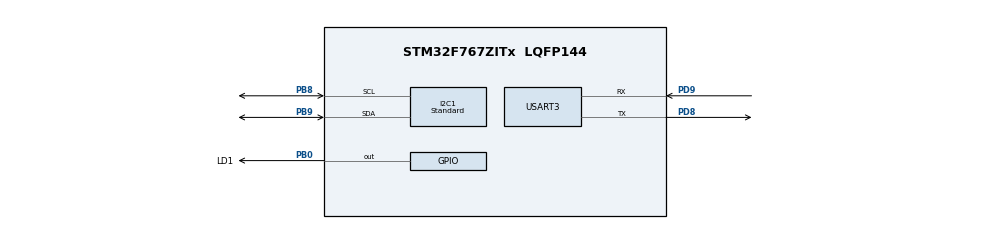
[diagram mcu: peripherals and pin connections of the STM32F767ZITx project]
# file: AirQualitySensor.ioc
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CORTEX_M7.default_mode_Activation=1
FREERTOS.Tasks01=MainApp,24,256,MainAppTask,Default,NULL,Dynamic,NULL,NULL
I2C1.I2C_Speed_Mode=I2C_Standard
I2C1.Timing=0x20404768
Mcu.Family=STM32F7
Mcu.Name=STM32F767ZITx
Mcu.Package=LQFP144
NVIC.PriorityGroup=NVIC_PRIORITYGROUP_4
NVIC.TIM6_DAC_IRQn=true\:15\:0\:false\:false\:true\:false\:false\:true\:true
NVIC.TimeBase=TIM6_DAC_IRQn
NVIC.TimeBaseIP=TIM6
PA13.Mode=Serial_Wire
PA13.Signal=SYS_JTMS-SWDIO
PA14.Mode=Serial_Wire
PA14.Signal=SYS_JTCK-SWCLK
PB0.GPIO_Label=LD1
PB0.Signal=GPIO_Output
PB8.GPIO_Mode=GPIO_MODE_AF_OD
PB8.GPIO_Pu=GPIO_NOPULL
PB8.Mode=I2C
PB8.Signal=I2C1_SCL
PB9.GPIO_Pu=GPIO_NOPULL
PB9.Mode=I2C
PB9.Signal=I2C1_SDA
PD8.Mode=Asynchronous
PD8.Signal=USART3_TX
PD9.Mode=Asynchronous
PD9.Signal=USART3_RX
PH0/OSC_IN.Mode=HSE-External-Clock-Source
PH0/OSC_IN.Signal=RCC_OSC_IN
PH1/OSC_OUT.Mode=HSE-External-Clock-Source
PH1/OSC_OUT.Signal=RCC_OSC_OUT
ProjectManager.HeapSize=0x200
ProjectManager.StackSize=0x400
ProjectManager.TargetToolchain=CMake
RCC.AHBFreq_Value=216000000
RCC.APB1CLKDivider=RCC_HCLK_DIV4
RCC.APB1Freq_Value=54000000
RCC.APB1TimFreq_Value=108000000
RCC.APB2CLKDivider=RCC_HCLK_DIV2
RCC.APB2Freq_Value=108000000
RCC.APB2TimFreq_Value=216000000
RCC.CortexFreq_Value=216000000
RCC.HCLKFreq_Value=216000000
RCC.HSE_VALUE=8000000
RCC.HSI_VALUE=16000000
RCC.LSE_VALUE=32768
RCC.PLLM=8
RCC.PLLN=432
RCC.PLLSourceVirtual=RCC_PLLSOURCE_HSE
RCC.SYSCLKFreq_VALUE=216000000
RCC.SYSCLKSource=RCC_SYSCLKSOURCE_PLLCLK
RCC.USBFreq_Value=216000000
RCC.VCOOutputFreq_Value=432000000
USART3.VirtualMode-Asynchronous=VM_ASYNC
VP_FREERTOS_VS_CMSIS_V2.Mode=CMSIS_V2
VP_RTC_VS_RTC_Activate.Mode=RTC_Enabled
VP_SYS_VS_tim6.Mode=TIM6
board=custom

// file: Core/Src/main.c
/* USER CODE BEGIN Header */
/**
  ******************************************************************************
  * @file           : main.c
  * @brief          : Main program body
  ******************************************************************************
  * @attention
  *
  * Copyright (c) 2026 STMicroelectronics.
  * All rights reserved.
  *
  * This software is licensed under terms that can be found in the LICENSE file
  * in the root directory of this software component.
  * If no LICENSE file comes with this software, it is provided AS-IS.
  *
  ******************************************************************************
  */
/* USER CODE END Header */
#include "main.h"
#include "cmsis_os.h"
#include "i2c.h"
#include "rtc.h"
#include "usart.h"
#include "gpio.h"

void SystemClock_Config(void);
static void MPU_Config(void);
void MX_FREERTOS_Init(void);

int main(void)
{

  /* MPU Configuration--------------------------------------------------------*/
  MPU_Config();

  /* MCU Configuration--------------------------------------------------------*/

  /* Reset of all peripherals, Initializes the Flash interface and the Systick. */
  HAL_Init();

  /* Configure the system clock */
  SystemClock_Config();

  /* Initialize all configured peripherals */
  MX_GPIO_Init();
  MX_RTC_Init();
  MX_USART3_UART_Init();
  MX_I2C1_Init();

  /* Init scheduler */
  osKernelInitialize();  /* Call init function for freertos objects (in cmsis_os2.c) */
  MX_FREERTOS_Init();

  /* Start scheduler */
  osKernelStart();

  /* We should never get here as control is now taken by the scheduler */

  /* Infinite loop */
  while (1)
  {

  }
}

void SystemClock_Config(void)
{
  RCC_OscInitTypeDef RCC_OscInitStruct = {0};
  RCC_ClkInitTypeDef RCC_ClkInitStruct = {0};

  /** Configure the main internal regulator output voltage
  */
  __HAL_RCC_PWR_CLK_ENABLE();
  __HAL_PWR_VOLTAGESCALING_CONFIG(PWR_REGULATOR_VOLTAGE_SCALE3);

  /** Initializes the RCC Oscillators according to the specified parameters
  * in the RCC_OscInitTypeDef structure.
  */
  RCC_OscInitStruct.OscillatorType = RCC_OSCILLATORTYPE_HSI|RCC_OSCILLATORTYPE_LSI;
  RCC_OscInitStruct.HSIState = RCC_HSI_ON;
  RCC_OscInitStruct.HSICalibrationValue = RCC_HSICALIBRATION_DEFAULT;
  RCC_OscInitStruct.LSIState = RCC_LSI_ON;
  RCC_OscInitStruct.PLL.PLLState = RCC_PLL_NONE;
  if (HAL_RCC_OscConfig(&RCC_OscInitStruct) != HAL_OK)
  {
    Error_Handler();
  }

  /** Initializes the CPU, AHB and APB buses clocks
  */
  RCC_ClkInitStruct.ClockType = RCC_CLOCKTYPE_HCLK|RCC_CLOCKTYPE_SYSCLK
                              |RCC_CLOCKTYPE_PCLK1|RCC_CLOCKTYPE_PCLK2;
  RCC_ClkInitStruct.SYSCLKSource = RCC_SYSCLKSOURCE_HSI;
  RCC_ClkInitStruct.AHBCLKDivider = RCC_SYSCLK_DIV1;
  RCC_ClkInitStruct.APB1CLKDivider = RCC_HCLK_DIV1;
  RCC_ClkInitStruct.APB2CLKDivider = RCC_HCLK_DIV1;

  if (HAL_RCC_ClockConfig(&RCC_ClkInitStruct, FLASH_LATENCY_0) != HAL_OK)
  {
    Error_Handler();
  }
}

 /* MPU Configuration */

void MPU_Config(void)
{
  MPU_Region_InitTypeDef MPU_InitStruct = {0};

  /* Disables the MPU */
  HAL_MPU_Disable();

  /** Initializes and configures the Region and the memory to be protected
  */
  MPU_InitStruct.Enable = MPU_REGION_ENABLE;
  MPU_InitStruct.Number = MPU_REGION_NUMBER0;
  MPU_InitStruct.BaseAddress = 0x0;
  MPU_InitStruct.Size = MPU_REGION_SIZE_4GB;
  MPU_InitStruct.SubRegionDisable = 0x87;
  MPU_InitStruct.TypeExtField = MPU_TEX_LEVEL0;
  MPU_InitStruct.AccessPermission = MPU_REGION_NO_ACCESS;
  MPU_InitStruct.DisableExec = MPU_INSTRUCTION_ACCESS_DISABLE;
  MPU_InitStruct.IsShareable = MPU_ACCESS_SHAREABLE;
  MPU_InitStruct.IsCacheable = MPU_ACCESS_NOT_CACHEABLE;
  MPU_InitStruct.IsBufferable = MPU_ACCESS_NOT_BUFFERABLE;

  HAL_MPU_ConfigRegion(&MPU_InitStruct);
  /* Enables the MPU */
  HAL_MPU_Enable(MPU_PRIVILEGED_DEFAULT);

}

void HAL_TIM_PeriodElapsedCallback(TIM_HandleTypeDef *htim)
{
  if (htim->Instance == TIM6)
  {
    HAL_IncTick();
  }
}

void Error_Handler(void)
{
  __disable_irq();
  while (1)
  {
  }
}

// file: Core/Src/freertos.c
/* USER CODE BEGIN Header */
/**
  ******************************************************************************
  * File Name          : freertos.c
  * Description        : Code for freertos applications
  ******************************************************************************
  * @attention
  *
  * Copyright (c) 2026 STMicroelectronics.
  * All rights reserved.
  *
  * This software is licensed under terms that can be found in the LICENSE file
  * in the root directory of this software component.
  * If no LICENSE file comes with this software, it is provided AS-IS.
  *
  ******************************************************************************
  */
/* USER CODE END Header */

#include "FreeRTOS.h"
#include "task.h"
#include "main.h"
#include "cmsis_os.h"

/* USER CODE BEGIN Includes */
#include "app_main.h"
/* USER CODE END Includes */

/* Definitions for StartDefault */
osThreadId_t StartDefaultHandle;
const osThreadAttr_t StartDefault_attributes = {
  .name = "StartDefault",
  .stack_size = 256 * 4,
  .priority = (osPriority_t) osPriorityNormal,
};

void StartDefaultTask(void *argument);

void MX_FREERTOS_Init(void); /* (MISRA C 2004 rule 8.1) */

void MX_FREERTOS_Init(void) {
  /* USER CODE BEGIN Init */
  app_main_init();
  /* USER CODE END Init */

  /* Create the thread(s) */
  /* creation of StartDefault */
  // StartDefaultHandle = osThreadNew(StartDefaultTask, NULL, &StartDefault_attributes);

}

// void StartDefaultTask(void *argument)
// {
//   /* USER CODE BEGIN StartDefaultTask */
//   /* Infinite loop */
//   for(;;)
//   {
//     osDelay(1);
//   }
//   /* USER CODE END StartDefaultTask */
// }
